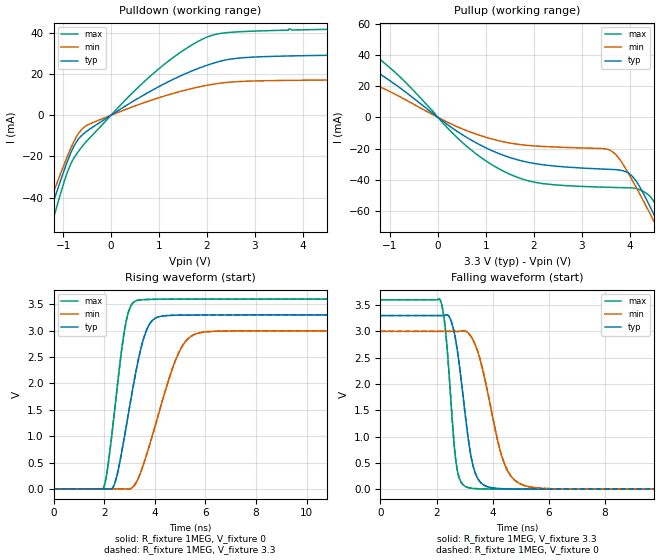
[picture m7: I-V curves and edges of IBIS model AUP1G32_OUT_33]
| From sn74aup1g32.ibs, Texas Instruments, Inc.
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[Model]   AUP1G32_OUT_33
Model_type  Output
Vref =   0
Rref =   1E6
Cref =   30p
Vmeas =   1.65
| variable   typ   min   max
C_comp   2.79pF   1.91pF   4.11pF
| C_pullup   3.16pF   1.91pF   4.11pF
| C_pulldown   2.42pF   2.21pF   2.99pF
[Temperature Range]   40   100   -40
| Ambient temperature   25   85   -40
[Voltage range]   3.3   3   3.6
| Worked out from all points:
|   slope of the pulldown table from 0 to 0.495 V, typ, clamps not added: 68.4 ohm
|   slope of the pullup table from 0 to 0.495 V, typ, clamps not added: 45.8 ohm
|   rising waveform, R_fixture 1MEG, V_fixture 0: 20-80 % time 764ps typ, 1.15ns min, 537ps max; typ from 0 V to 3.3 V
|   falling waveform, R_fixture 1MEG, V_fixture 3.3: 20-80 % time 476ps typ, 758ps min, 306ps max; typ from 3.3 V to 0 V
|   rising waveform, R_fixture 1MEG, V_fixture 3.3: 20-80 % time 763ps typ, 1.14ns min, 537ps max; typ from 0 V to 3.3 V
|   falling waveform, R_fixture 1MEG, V_fixture 0: 20-80 % time 476ps typ, 757ps min, 306ps max; typ from 3.3 V to 0 V
[Pulldown]
| AUP1G32_OUT_33
|   Voltage   I(typ)   I(min)   I(max)
-3.6V     -218.7mA   -196.3mA   -248.6mA
-1.515V   -64.37mA   -57.31mA   -75.82mA
-1.39V    -55.35mA   -49.29mA   -65.41mA
-1.275V   -47.14mA   -42mA      -55.89mA
-870mV    -19.93mA   -17.62mA   -25.18mA
-720mV    -12.85mA   -10.38mA   -18.82mA
-545mV    -8.444mA   -5.509mA   -13.51mA
940mV     13.13mA    8.018mA    21.36mA
1.5V      19.56mA    11.86mA    31.27mA
2.045V    24.53mA    14.67mA    38.2mA
3.1V      28.27mA    16.63mA    40.81mA
7.2V      29.73mA    17.36mA    42.67mA
[Pullup]
| AUP1G32_OUT_33
|   Voltage   I(typ)   I(min)   I(max)
-3.6V     42.87mA    27.21mA    57.96mA
-2.465V   31.52mA    19.46mA    45.92mA
-1.53V    32.86mA    22.06mA    44.96mA
-755mV    18.1mA     12.64mA    24.89mA
555mV     -11.98mA   -7.942mA   -17.3mA
1.65V     -27.07mA   -17.13mA   -38.31mA
3.61V     -33.32mA   -21.39mA   -44.82mA
4.08V     -38.63mA   -41.77mA   -45.28mA
4.375V    -54.25mA   -58.9mA    -49.24mA
4.565V    -66.24mA   -70.37mA   -57.33mA
4.775V    -80.02mA   -83.29mA   -71.37mA
7.2V      -250.7mA   -240.9mA   -257mA
[Ramp]
| AUP1G32_OUT_33
| variable   typ   min   max
dV/dt_r   1.98/7.65E-10   1.80/1.15E-09   2.16/5.38E-10
dV/dt_f   1.99/4.80E-10   1.81/7.63E-10   2.17/3.11E-10
R_load = 1MEG
[Rising Waveform]
| AUP1G32_OUT_33
R_fixture =   1MEG
C_fixture =   0
L_fixture =   0
V_fixture =   0
V_fixture_min = 0
V_fixture_max = 0
|   Time   V(typ)   V(min)   V(max)
0s        27.98nV    100.1nV    2.29nV
1.98ns    -66.42uV   3.044uV    25.81mV
2.4ns     81.9mV     -172.2uV   1.428V
2.825ns   1.053V     575.1uV    3.062V
3.295ns   2.319V     146.4mV    3.573V
3.625ns   2.947V     569.7mV    3.591V
3.955ns   3.215V     1.094V     3.595V
4.945ns   3.294V     2.578V     3.598V
5.775ns   3.297V     2.961V     3.599V
29.99ns   3.3V       3V         3.6V
[Falling Waveform]
| AUP1G32_OUT_33
R_fixture =   1MEG
C_fixture =   0
L_fixture =   0
V_fixture =   3.3
V_fixture_min = 3
V_fixture_max = 3.6
|   Time   V(typ)   V(min)   V(max)
0s        3.3V       3V         3.6V
2.135ns   3.3V       3V         3.592V
2.33ns    3.311V     3V         2.962V
2.515ns   3.203V     3V         1.667V
2.71ns    2.745V     2.998V     456.7mV
3.15ns    882.7mV    2.957V     27.1mV
3.535ns   149.4mV    2.499V     6.371mV
4.425ns   6.517mV    475.7mV    550.6uV
5.305ns   889.4uV    45.59mV    190.4uV
29.99ns   216.3uV    319.9uV    141.3uV
[Rising Waveform]
| AUP1G32_OUT_33
R_fixture =   1MEG
C_fixture =   0
L_fixture =   0
V_fixture =   3.3
V_fixture_min = 3
V_fixture_max = 3.6
|   Time   V(typ)   V(min)   V(max)
0s        216.3uV    319.9uV    141.3uV
1.98ns    149.9uV    322.8uV    25.96mV
2.4ns     82.16mV    147.6uV    1.429V
2.825ns   1.054V     895uV      3.063V
3.295ns   2.32V      146.8mV    3.573V
3.625ns   2.947V     570.6mV    3.591V
3.955ns   3.215V     1.095V     3.595V
4.945ns   3.294V     2.579V     3.598V
5.775ns   3.297V     2.961V     3.599V
29.99ns   3.3V       3V         3.6V
[Falling Waveform]
| AUP1G32_OUT_33
R_fixture =   1MEG
C_fixture =   0
L_fixture =   0
V_fixture =   0
V_fixture_min = 0
V_fixture_max = 0
|   Time   V(typ)   V(min)   V(max)
0s        3.3V       3V         3.6V
2.135ns   3.3V       3V         3.591V
2.33ns    3.311V     3V         2.962V
2.515ns   3.203V     3V         1.667V
2.71ns    2.744V     2.998V     456.2mV
3.15ns    882mV      2.957V     26.94mV
3.535ns   149.1mV    2.498V     6.225mV
4.425ns   6.288mV    474.9mV    408.7uV
5.305ns   670.4uV    45.13mV    49.02uV
29.99ns   1.599nV    86.09nV    -14.25nV
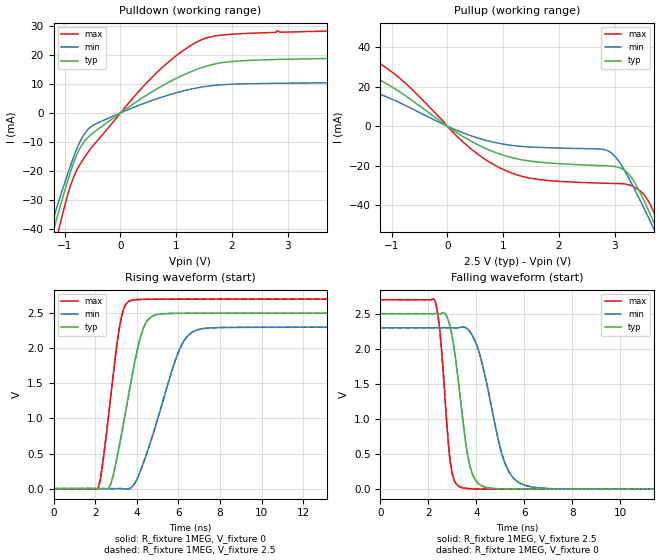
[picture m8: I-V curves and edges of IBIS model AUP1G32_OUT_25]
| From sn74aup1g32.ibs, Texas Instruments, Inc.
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[Model]   AUP1G32_OUT_25
Model_type  Output
Vref =   0
Rref =   1E6
Cref =   30p
Vmeas =   1.25
| variable   typ   min   max
C_comp   2.83pF   1.96pF   4.14pF
| C_pullup   3.16pF   1.96pF   4.14pF
| C_pulldown   2.51pF   2.22pF   3.08pF
[Temperature Range]   40   100   -40
| Ambient temperature   25   85   -40
[Voltage range]   2.5   2.3   2.7
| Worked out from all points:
|   slope of the pulldown table from 0 to 0.375 V, typ, clamps not added: 75.2 ohm
|   slope of the pullup table from 0 to 0.375 V, typ, clamps not added: 55.1 ohm
|   rising waveform, R_fixture 1MEG, V_fixture 0: 20-80 % time 957ps typ, 1.44ns min, 656ps max; typ from 0 V to 2.5 V
|   falling waveform, R_fixture 1MEG, V_fixture 2.5: 20-80 % time 558ps typ, 899ps min, 360ps max; typ from 2.5 V to 0 V
|   rising waveform, R_fixture 1MEG, V_fixture 2.5: 20-80 % time 957ps typ, 1.44ns min, 656ps max; typ from 0 V to 2.5 V
|   falling waveform, R_fixture 1MEG, V_fixture 0: 20-80 % time 558ps typ, 899ps min, 360ps max; typ from 2.5 V to 0 V
[Pulldown]
| AUP1G32_OUT_25
|   Voltage   I(typ)   I(min)   I(max)
-3.6V     -214mA     -193.5mA   -239.7mA
-1.26V    -44.55mA   -39.92mA   -52.42mA
-1.205V   -40.74mA   -36.52mA   -48.02mA
-1.115V   -34.57mA   -31.02mA   -40.91mA
-800mV    -15.22mA   -13.22mA   -20.4mA
-685mV    -10.84mA   -8.445mA   -16.54mA
-540mV    -7.689mA   -4.911mA   -12.5mA
675mV     8.558mA    5.038mA    14.35mA
1.105V    12.9mA     7.5mA      21.28mA
1.52V     16.03mA    9.129mA    25.76mA
2.805V    18.45mA    10.24mA    28.28mA
7.2V      19.61mA    10.73mA    29.61mA
[Pullup]
| AUP1G32_OUT_25
|   Voltage   I(typ)   I(min)   I(max)
-3.6V     37.27mA    23.46mA    50.39mA
-2.36V    24.67mA    15.19mA    35.64mA
-1.425V   26mA       17.18mA    35.59mA
-760mV    15.58mA    10.62mA    21.96mA
405mV     -7.279mA   -4.651mA   -11.04mA
1.05V     -15.07mA   -9.293mA   -22.54mA
2.845V    -20.04mA   -12.07mA   -28.88mA
3.17V     -22.17mA   -22.09mA   -29.2mA
3.455V    -33.67mA   -37.48mA   -32.73mA
3.685V    -47.61mA   -50.92mA   -42.5mA
3.82V     -56.28mA   -59.04mA   -51.47mA
7.2V      -294.7mA   -278.7mA   -311.5mA
[Ramp]
| AUP1G32_OUT_25
| variable   typ   min   max
dV/dt_r   1.50/9.61E-10   1.38/1.45E-09   1.62/6.58E-10
dV/dt_f   1.51/5.64E-10   1.39/9.07E-10   1.63/3.64E-10
R_load = 1MEG
[Rising Waveform]
| AUP1G32_OUT_25
R_fixture =   1MEG
C_fixture =   0
L_fixture =   0
V_fixture =   0
V_fixture_min = 0
V_fixture_max = 0
|   Time   V(typ)   V(min)   V(max)
0s        21.76nV    95.42nV    1.586nV
2.155ns   -85.48uV   3.158uV    20.35mV
2.705ns   35.71mV    -150.9uV   1.194V
3.18ns    635.7mV    1.828mV    2.314V
3.725ns   1.522V     13.5mV     2.68V
4.19ns    2.167V     263.2mV    2.695V
4.59ns    2.422V     597.5mV    2.697V
6.045ns   2.497V     1.973V     2.699V
6.975ns   2.498V     2.266V     2.7V
32ns      2.5V       2.3V       2.7V
[Falling Waveform]
| AUP1G32_OUT_25
R_fixture =   1MEG
C_fixture =   0
L_fixture =   0
V_fixture =   2.5
V_fixture_min = 2.3
V_fixture_max = 2.7
|   Time   V(typ)   V(min)   V(max)
0s        2.5V       2.3V       2.7V
2.27ns    2.5V       2.3V       2.688V
2.485ns   2.499V     2.3V       2.234V
2.94ns    2.263V     2.3V       328.2mV
3.435ns   996.6mV    2.311V     19.24mV
3.71ns    366.9mV    2.254V     7.239mV
4.04ns    95.23mV    2.03V      2.585mV
5.18ns    3.119mV    384.6mV    214.1uV
6.18ns    482.4uV    40.71mV    124.8uV
32ns      178.6uV    276uV      112.4uV
[Rising Waveform]
| AUP1G32_OUT_25
R_fixture =   1MEG
C_fixture =   0
L_fixture =   0
V_fixture =   2.5
V_fixture_min = 2.3
V_fixture_max = 2.7
|   Time   V(typ)   V(min)   V(max)
0s        178.6uV    276.1uV    112.4uV
2.155ns   93.1uV     279.2uV    20.47mV
2.705ns   35.92mV    125uV      1.195V
3.18ns    636.4mV    2.104mV    2.315V
3.725ns   1.523V     13.81mV    2.68V
4.19ns    2.168V     263.9mV    2.695V
4.59ns    2.422V     598.7mV    2.697V
6.045ns   2.497V     1.974V     2.699V
6.975ns   2.499V     2.267V     2.7V
32ns      2.5V       2.3V       2.7V
[Falling Waveform]
| AUP1G32_OUT_25
R_fixture =   1MEG
C_fixture =   0
L_fixture =   0
V_fixture =   0
V_fixture_min = 0
V_fixture_max = 0
|   Time   V(typ)   V(min)   V(max)
0s        2.5V       2.3V       2.7V
2.27ns    2.5V       2.3V       2.688V
2.485ns   2.499V     2.3V       2.234V
2.94ns    2.263V     2.3V       327.9mV
3.435ns   996mV      2.311V     19.12mV
3.71ns    366.5mV    2.254V     7.12mV
4.04ns    94.95mV    2.03V      2.47mV
5.18ns    2.932mV    383.9mV    101.4uV
6.18ns    302uV      40.25mV    12.4uV
32ns      -2.304nV   29.56nV    -15.94nV
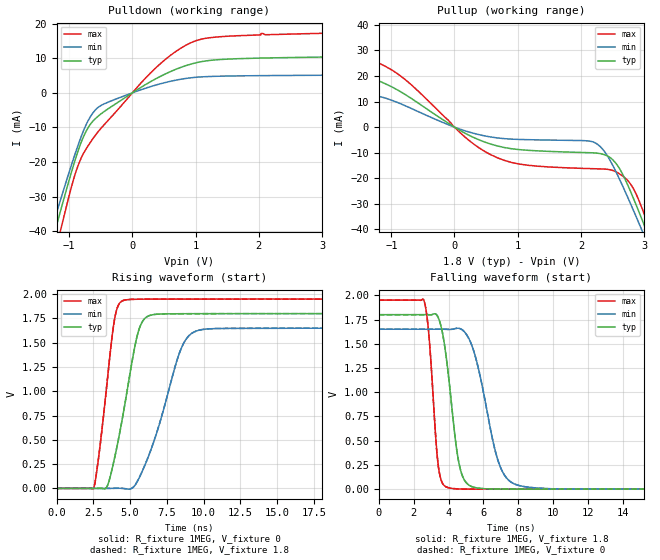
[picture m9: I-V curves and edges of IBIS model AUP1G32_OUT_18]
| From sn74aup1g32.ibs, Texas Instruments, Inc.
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[Model]   AUP1G32_OUT_18
Model_type  Output
Vref =   0
Rref =   1E6
Cref =   30p
Vmeas =   0.9
| variable   typ   min   max
C_comp   2.87pF   2.03pF   4.09pF
| C_pullup   3.13pF   2.03pF   4.09pF
| C_pulldown   2.60pF   2.23pF   3.12pF
[Temperature Range]   40   100   -40
| Ambient temperature   25   85   -40
[Voltage range]   1.8   1.65   1.95
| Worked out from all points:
|   slope of the pulldown table from 0 to 0.27 V, typ, clamps not added: 88.6 ohm
|   slope of the pullup table from 0 to 0.27 V, typ, clamps not added: 73.6 ohm
|   rising waveform, R_fixture 1MEG, V_fixture 0: 20-80 % time 1.28ns typ, 1.94ns min, 857ps max; typ from 0 V to 1.8 V
|   falling waveform, R_fixture 1MEG, V_fixture 1.8: 20-80 % time 699ps typ, 1.17ns min, 439ps max; typ from 1.8 V to 0 V
|   rising waveform, R_fixture 1MEG, V_fixture 1.8: 20-80 % time 1.28ns typ, 1.94ns min, 857ps max; typ from 0 V to 1.8 V
|   falling waveform, R_fixture 1MEG, V_fixture 0: 20-80 % time 699ps typ, 1.17ns min, 439ps max; typ from 1.8 V to 0 V
[Pulldown]
| AUP1G32_OUT_18
|   Voltage   I(typ)   I(min)   I(max)
-3.6V     -208.6mA   -189.9mA   -231.7mA
-1.27V    -43.16mA   -39.01mA   -50.14mA
-1.215V   -39.42mA   -35.66mA   -45.88mA
-1.125V   -33.38mA   -30.25mA   -38.97mA
-850mV    -16.31mA   -14.68mA   -20.63mA
-710mV    -10.41mA   -8.408mA   -15.6mA
-555mV    -6.973mA   -4.411mA   -11.55mA
360mV     3.96mA     2.185mA    7.039mA
705mV     6.927mA    3.722mA    12.18mA
1.03V     8.784mA    4.527mA    15.22mA
2.045V    10.05mA    4.967mA    17.16mA
7.2V      11.18mA    5.355mA    18.77mA
[Pullup]
| AUP1G32_OUT_18
|   Voltage   I(typ)   I(min)   I(max)
-3.6V     32.08mA    19.68mA    43.87mA
-3.16V    27.18mA    16.59mA    37.99mA
-2.12V    17.93mA    10.75mA    26.53mA
-1.525V   19.28mA    11.75mA    27.77mA
-1.155V   17.65mA    11.81mA    24.55mA
680mV     -7.373mA   -4.228mA   -12mA
2.185V    -10.05mA   -5.721mA   -16.26mA
2.485V    -12.35mA   -14.1mA    -16.81mA
2.725V    -21.81mA   -26.61mA   -20.47mA
2.94V     -34.55mA   -38.91mA   -30.08mA
3.085V    -43.74mA   -47.5mA    -39.77mA
7.2V      -334.8mA   -315.6mA   -357.6mA
[Ramp]
| AUP1G32_OUT_18
| variable   typ   min   max
dV/dt_r   1.08/1.29E-09   0.99/1.96E-09   1.17/8.60E-10
dV/dt_f   1.09/7.06E-10   1.00/1.18E-09   1.18/4.47E-10
R_load = 1MEG
[Rising Waveform]
| AUP1G32_OUT_18
R_fixture =   1MEG
C_fixture =   0
L_fixture =   0
V_fixture =   0
V_fixture_min = 0
V_fixture_max = 0
|   Time   V(typ)   V(min)   V(max)
0s        18.54nV    100.1nV    1.179nV
2.54ns    -93.92uV   3.907uV    10.53mV
3.39ns    8.296mV    -118.8uV   1.021V
3.905ns   282.8mV    695.5uV    1.702V
4.525ns   760.3mV    -515.6uV   1.935V
5.385ns   1.505V     43.32mV    1.948V
5.905ns   1.733V     201.9mV    1.949V
8.41ns    1.799V     1.415V     1.95V
9.5ns     1.799V     1.621V     1.95V
34ns      1.8V       1.65V      1.95V
[Falling Waveform]
| AUP1G32_OUT_18
R_fixture =   1MEG
C_fixture =   0
L_fixture =   0
V_fixture =   1.8
V_fixture_min = 1.65
V_fixture_max = 1.95
|   Time   V(typ)   V(min)   V(max)
0s        1.8V       1.65V      1.95V
2.6ns     1.8V       1.65V      1.943V
2.875ns   1.799V     1.65V      1.593V
3.415ns   1.768V     1.65V      241.2mV
3.96ns    1.228V     1.648V     16.81mV
4.49ns    379.8mV    1.66V      3.41mV
4.91ns    92.97mV    1.623V     1.042mV
6.87ns    893.4uV    274.3mV    98.75uV
7.94ns    248.3uV    42.33mV    91.74uV
34ns      149.3uV    244.2uV    89.89uV
[Rising Waveform]
| AUP1G32_OUT_18
R_fixture =   1MEG
C_fixture =   0
L_fixture =   0
V_fixture =   1.8
V_fixture_min = 1.65
V_fixture_max = 1.95
|   Time   V(typ)   V(min)   V(max)
0s        149.3uV    244uV      89.92uV
2.54ns    55.38uV    247.8uV    10.64mV
3.39ns    8.482mV    125.1uV    1.022V
3.905ns   283.3mV    939.5uV    1.703V
4.525ns   761.2mV    -272.5uV   1.935V
5.38ns    1.502V     42.59mV    1.948V
5.9ns     1.732V     200.9mV    1.949V
8.41ns    1.799V     1.416V     1.95V
9.5ns     1.799V     1.621V     1.95V
34ns      1.8V       1.65V      1.95V
[Falling Waveform]
| AUP1G32_OUT_18
R_fixture =   1MEG
C_fixture =   0
L_fixture =   0
V_fixture =   0
V_fixture_min = 0
V_fixture_max = 0
|   Time   V(typ)   V(min)   V(max)
0s        1.8V       1.65V      1.95V
2.6ns     1.8V       1.65V      1.943V
2.875ns   1.799V     1.65V      1.592V
3.415ns   1.768V     1.65V      240.9mV
3.96ns    1.227V     1.648V     16.71mV
4.49ns    379.3mV    1.66V      3.315mV
4.91ns    92.7mV     1.623V     950.2uV
6.87ns    739.9uV    273.8mV    8.78uV
7.94ns    98.09uV    41.9mV     1.807uV
34ns      -28.35nV   253.6nV    -31.24nV
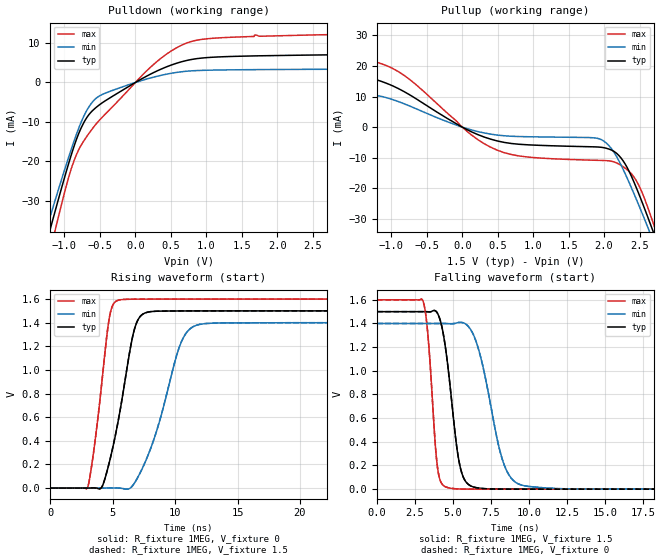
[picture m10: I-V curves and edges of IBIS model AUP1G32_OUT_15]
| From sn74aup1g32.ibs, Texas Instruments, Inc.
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[Model]   AUP1G32_OUT_15
Model_type  Output
Vref =   0
Rref =   1E6
Cref =   30p
Vmeas =   0.75
| variable   typ   min   max
C_comp   2.87pF   2.09pF   4.01pF
| C_pullup   3.08pF   2.09pF   4.01pF
| C_pulldown   2.65pF   2.24pF   3.14pF
[Temperature Range]   40   100   -40
| Ambient temperature   25   85   -40
[Voltage range]   1.5   1.4   1.6
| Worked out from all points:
|   slope of the pulldown table from 0 to 0.225 V, typ, clamps not added: 101 ohm
|   slope of the pullup table from 0 to 0.225 V, typ, clamps not added: 90.4 ohm
|   rising waveform, R_fixture 1MEG, V_fixture 0: 20-80 % time 1.53ns typ, 2.27ns min, 1.03ns max; typ from 0 V to 1.5 V
|   falling waveform, R_fixture 1MEG, V_fixture 1.5: 20-80 % time 813ps typ, 1.37ns min, 506ps max; typ from 1.5 V to 0 V
|   rising waveform, R_fixture 1MEG, V_fixture 1.5: 20-80 % time 1.53ns typ, 2.27ns min, 1.03ns max; typ from 0 V to 1.5 V
|   falling waveform, R_fixture 1MEG, V_fixture 0: 20-80 % time 813ps typ, 1.37ns min, 506ps max; typ from 1.5 V to 0 V
[Pulldown]
| AUP1G32_OUT_15
|   Voltage   I(typ)   I(min)   I(max)
-3.6V     -206.1mA   -188.4mA   -227.8mA
-1.265V   -41.59mA   -37.94mA   -47.65mA
-1.21V    -37.9mA    -34.62mA   -43.48mA
-1.11V    -31.29mA   -28.67mA   -36mA
-945mV    -20.84mA   -19.21mA   -24.37mA
-855mV    -15.7mA    -14.39mA   -19.43mA
-720mV    -9.972mA   -8.297mA   -14.65mA
-570mV    -6.595mA   -4.269mA   -10.91mA
260mV     2.544mA    1.373mA    4.642mA
810mV     5.906mA    2.979mA    10.53mA
1.69V     6.763mA    3.269mA    12.06mA
7.2V      7.827mA    3.609mA    13.77mA
[Pullup]
| AUP1G32_OUT_15
|   Voltage   I(typ)   I(min)   I(max)
-3.6V     29.66mA    17.92mA    40.73mA
-2.925V   22.54mA    13.62mA    31.92mA
-2.13V    15.77mA    9.482mA    23.18mA
-1.075V   14.38mA    9.657mA    20.14mA
130mV     -1.525mA   -910.1uA   -2.565mA
590mV     -4.979mA   -2.819mA   -8.32mA
1.925V    -6.506mA   -3.765mA   -10.85mA
2.175V    -8.513mA   -9.57mA    -11.67mA
2.395V    -16.55mA   -20.31mA   -15.49mA
2.615V    -29.32mA   -32.63mA   -26.15mA
2.72V     -35.89mA   -38.74mA   -33.2mA
7.2V      -352.6mA   -330.3mA   -379.5mA
[Ramp]
| AUP1G32_OUT_15
| variable   typ   min   max
dV/dt_r   0.90/1.54E-09   0.85/2.30E-09   0.96/1.04E-09
dV/dt_f   0.91/8.23E-10   0.85/1.38E-09   0.96/5.13E-10
R_load = 1MEG
[Rising Waveform]
| AUP1G32_OUT_15
R_fixture =   1MEG
C_fixture =   0
L_fixture =   0
V_fixture =   0
V_fixture_min = 0
V_fixture_max = 0
|   Time   V(typ)   V(min)   V(max)
0s        18.11nV    107.8nV    1.037nV
3.005ns   -94.98uV   957.3nV    9.569mV
4.08ns    1.214mV    -121.4uV   843.6mV
4.695ns   202.7mV    740.6uV    1.417V
5.37ns    528.2mV    598.8uV    1.587V
6.54ns    1.253V     12.5mV     1.599V
7.12ns    1.441V     112.2mV    1.599V
10.39ns   1.499V     1.207V     1.6V
11.61ns   1.5V       1.374V     1.6V
38ns      1.5V       1.4V       1.6V
[Falling Waveform]
| AUP1G32_OUT_15
R_fixture =   1MEG
C_fixture =   0
L_fixture =   0
V_fixture =   1.5
V_fixture_min = 1.4
V_fixture_max = 1.6
|   Time   V(typ)   V(min)   V(max)
0s        1.5V       1.4V       1.6V
3.025ns   1.5V       1.4V       1.588V
3.355ns   1.499V     1.4V       1.287V
3.965ns   1.488V     1.4V       194.1mV
4.59ns    1.111V     1.399V     15.45mV
5.765ns   78.02mV    1.401V     700.8uV
6.715ns   8.85mV     1.166V     135uV
8.315ns   541.2uV    224.6mV    83.1uV
9.46ns    195.2uV    36.33mV    81.22uV
38ns      139.7uV    237.8uV    80.72uV
[Rising Waveform]
| AUP1G32_OUT_15
R_fixture =   1MEG
C_fixture =   0
L_fixture =   0
V_fixture =   1.5
V_fixture_min = 1.4
V_fixture_max = 1.6
|   Time   V(typ)   V(min)   V(max)
0s        139.7uV    237.8uV    80.77uV
3.005ns   44.69uV    238.6uV    9.687mV
4.08ns    1.402mV    116.3uV    844.3mV
4.695ns   203.2mV    978.2uV    1.418V
5.37ns    529.2mV    834.4uV    1.587V
6.54ns    1.254V     12.93mV    1.599V
7.12ns    1.441V     113mV      1.599V
10.39ns   1.499V     1.208V     1.6V
11.61ns   1.5V       1.375V     1.6V
38ns      1.5V       1.4V       1.6V
[Falling Waveform]
| AUP1G32_OUT_15
R_fixture =   1MEG
C_fixture =   0
L_fixture =   0
V_fixture =   0
V_fixture_min = 0
V_fixture_max = 0
|   Time   V(typ)   V(min)   V(max)
0s        1.5V       1.4V       1.6V
3.025ns   1.5V       1.4V       1.588V
3.355ns   1.499V     1.4V       1.286V
3.965ns   1.488V     1.4V       193.9mV
4.59ns    1.11V      1.399V     15.36mV
5.765ns   77.76mV    1.401V     618.7uV
6.715ns   8.672mV    1.165V     53.95uV
8.315ns   398.5uV    224mV      2.312uV
9.46ns    54.99uV    36.04mV    444.5nV
38ns      89.79nV    146.6nV    -48.35nV
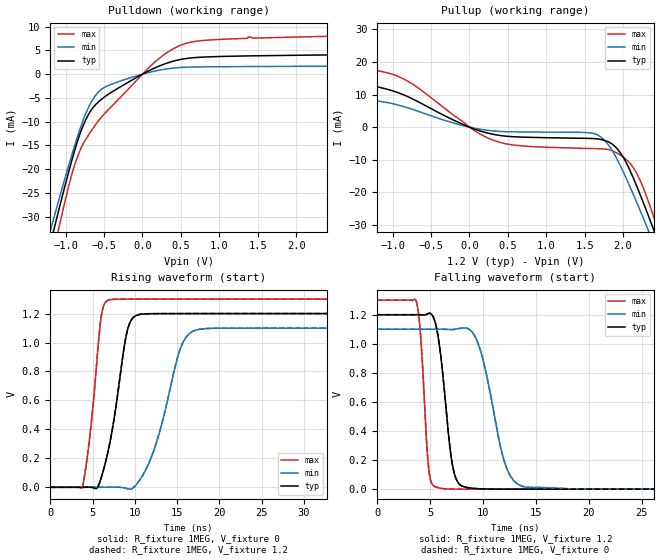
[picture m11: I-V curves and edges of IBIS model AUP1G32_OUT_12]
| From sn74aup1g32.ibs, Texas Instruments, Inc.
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[Model]   AUP1G32_OUT_12
Model_type  Output
Vref =   0
Rref =   1E6
Cref =   30p
Vmeas =   0.6
| variable   typ   min   max
C_comp   2.83pF   2.12pF   3.87pF
| C_pullup   3.00pF   2.12pF   3.87pF
| C_pulldown   2.67pF   2.23pF   3.17pF
[Temperature Range]   40   100   -40
| Ambient temperature   25   85   -40
[Voltage range]   1.2   1.1   1.3
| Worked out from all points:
|   slope of the pulldown table from 0 to 0.18 V, typ, clamps not added: 125 ohm
|   slope of the pullup table from 0 to 0.18 V, typ, clamps not added: 123 ohm
|   rising waveform, R_fixture 1MEG, V_fixture 0: 20-80 % time 1.91ns typ, 2.94ns min, 1.28ns max; typ from 0 V to 1.2 V
|   falling waveform, R_fixture 1MEG, V_fixture 1.2: 20-80 % time 1.02ns typ, 1.86ns min, 609ps max; typ from 1.2 V to 0 V
|   rising waveform, R_fixture 1MEG, V_fixture 1.2: 20-80 % time 1.91ns typ, 2.94ns min, 1.28ns max; typ from 0 V to 1.2 V
|   falling waveform, R_fixture 1MEG, V_fixture 0: 20-80 % time 1.02ns typ, 1.86ns min, 609ps max; typ from 1.2 V to 0 V
[Pulldown]
| AUP1G32_OUT_12
|   Voltage   I(typ)   I(min)   I(max)
-3.6V     -203.6mA   -186.6mA   -224.6mA
-1.215V   -36.77mA   -33.88mA   -41.55mA
-1.165V   -33.49mA   -30.92mA   -37.89mA
-1.08V    -28mA      -25.95mA   -31.76mA
-930mV    -18.76mA   -17.53mA   -21.68mA
-835mV    -13.58mA   -12.59mA   -16.93mA
-695mV    -8.261mA   -6.747mA   -12.62mA
-560mV    -5.647mA   -3.535mA   -9.551mA
195mV     1.548mA    762.4uA    3.019mA
610mV     3.376mA    1.481mA    6.659mA
1.385V    3.84mA     1.603mA    7.836mA
7.2V      4.761mA    1.852mA    9.574mA
[Pullup]
| AUP1G32_OUT_12
|   Voltage   I(typ)   I(min)   I(max)
-3.6V     26.64mA    8.231mA    37.82mA
-3.07V    21.45mA    10.47mA    31mA
-2.05V    13.05mA    7.514mA    19.68mA
-955mV    10.79mA    6.947mA    15.81mA
400mV     -2.561mA   -1.314mA   -4.679mA
1.61V     -3.491mA   -1.891mA   -6.566mA
1.87V     -5.387mA   -7.563mA   -7.321mA
2.095V    -13.49mA   -18.49mA   -11.17mA
2.33V     -27.16mA   -31.66mA   -22.8mA
2.44V     -34.07mA   -38.08mA   -30.25mA
2.51V     -38.55mA   -42.22mA   -35.17mA
7.2V      -371mA     -348.5mA   -398.6mA
[Ramp]
| AUP1G32_OUT_12
| variable   typ   min   max
dV/dt_r   0.73/1.93E-09   0.67/3.00E-09   0.78/1.28E-09
dV/dt_f   0.73/1.03E-09   0.67/1.88E-09   0.78/6.17E-10
R_load = 1MEG
[Rising Waveform]
| AUP1G32_OUT_12
R_fixture =   1MEG
C_fixture =   0
L_fixture =   0
V_fixture =   0
V_fixture_min = 0
V_fixture_max = 0
|   Time   V(typ)   V(min)   V(max)
0s        18.95nV    130.2nV    950.7pV
3.815ns   -74.41uV   262.2nV    5.371mV
5.995ns   60.21mV    -130.5uV   1.164V
6.845ns   250mV      661.8uV    1.292V
9.01ns    1.055V     -7.854mV   1.3V
10.33ns   1.19V      29.93mV    1.3V
12.54ns   1.199V     304.7mV    1.3V
15.41ns   1.2V       961.5mV    1.3V
17.1ns    1.2V       1.083V     1.3V
60ns      1.2V       1.1V       1.3V
[Falling Waveform]
| AUP1G32_OUT_12
R_fixture =   1MEG
C_fixture =   0
L_fixture =   0
V_fixture =   1.2
V_fixture_min = 1.1
V_fixture_max = 1.3
|   Time   V(typ)   V(min)   V(max)
0s        1.2V       1.1V       1.3V
3.7ns     1.2V       1.1V       1.292V
4.87ns    1.209V     1.1V       140.9mV
5.64ns    1.098V     1.1V       12.67mV
7.095ns   174.5mV    1.098V     530.8uV
8.23ns    15.55mV    1.109V     105.8uV
9.765ns   2.283mV    952.1mV    76.42uV
12.18ns   188.2uV    155.4mV    74.88uV
13.76ns   140.5uV    18.92mV    74.79uV
60ns      135uV      244.3uV    74.83uV
[Rising Waveform]
| AUP1G32_OUT_12
R_fixture =   1MEG
C_fixture =   0
L_fixture =   0
V_fixture =   1.2
V_fixture_min = 1.1
V_fixture_max = 1.3
|   Time   V(typ)   V(min)   V(max)
0s        135uV      244.2uV    74.83uV
3.815ns   60.66uV    244.3uV    5.507mV
5.995ns   60.66mV    113.8uV    1.165V
6.845ns   250.9mV    905.2uV    1.292V
9.01ns    1.056V     -7.58mV    1.3V
10.33ns   1.191V     30.69mV    1.3V
12.53ns   1.199V     305.5mV    1.3V
15.41ns   1.2V       961.4mV    1.3V
17.09ns   1.2V       1.083V     1.3V
60ns      1.2V       1.1V       1.3V
[Falling Waveform]
| AUP1G32_OUT_12
R_fixture =   1MEG
C_fixture =   0
L_fixture =   0
V_fixture =   0
V_fixture_min = 0
V_fixture_max = 0
|   Time   V(typ)   V(min)   V(max)
0s        1.2V       1.1V       1.3V
3.7ns     1.2V       1.1V       1.291V
4.865ns   1.209V     1.1V       144mV
5.64ns    1.098V     1.1V       12.58mV
7.095ns   174.1mV    1.098V     455uV
8.23ns    15.36mV    1.109V     30.82uV
9.76ns    2.143mV    952.4mV    1.582uV
12.18ns   52.53uV    154.6mV    48.95nV
13.76ns   5.394uV    18.75mV    -44.72nV
60ns      7.983nV    205.1nV    -3.29nV
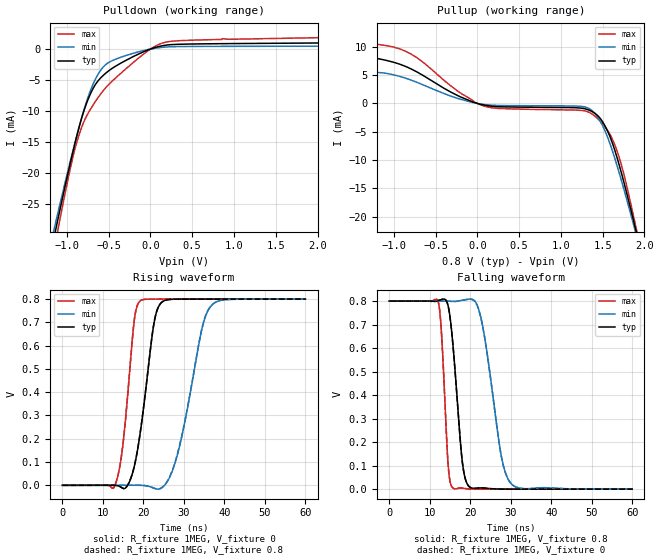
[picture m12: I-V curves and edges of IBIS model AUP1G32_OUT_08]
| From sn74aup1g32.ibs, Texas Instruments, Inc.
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[Model]   AUP1G32_OUT_08
Model_type  Output
Vref =   0
Rref =   1E6
Cref =   30p
Vmeas =   0.4
| variable   typ   min   max
C_comp   2.70pF   2.19pF   3.31pF
| C_pullup   2.75pF   2.20pF   3.31pF
| C_pulldown   2.64pF   2.19pF   3.08pF
[Temperature Range]   40   100   -40
| Ambient temperature   25   85   -40
[Voltage range]   0.8   0.8   0.8
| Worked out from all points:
|   slope of the pulldown table from 0 to 0.12 V, typ, clamps not added: 257 ohm
|   slope of the pullup table from 0 to 0.12 V, typ, clamps not added: 309 ohm
|   rising waveform, R_fixture 1MEG, V_fixture 0: 20-80 % time 3.5ns typ, 5.26ns min, 2.5ns max; typ from 0 V to 0.8 V
|   falling waveform, R_fixture 1MEG, V_fixture 0.8: 20-80 % time 2.19ns typ, 3.87ns min, 1.35ns max; typ from 0.8 V to 0 V
|   rising waveform, R_fixture 1MEG, V_fixture 0.8: 20-80 % time 3.5ns typ, 5.25ns min, 2.5ns max; typ from 0 V to 0.8 V
|   falling waveform, R_fixture 1MEG, V_fixture 0: 20-80 % time 2.19ns typ, 3.87ns min, 1.35ns max; typ from 0.8 V to 0 V
[Pulldown]
| AUP1G32_OUT_08
|   Voltage   I(typ)   I(min)   I(max)
-3.6V     -200.3mA   -184.7mA   -219.1mA
-1.155V   -30.43mA   -29.11mA   -32.45mA
-1.105V   -27.26mA   -26.22mA   -28.93mA
-940mV    -17.24mA   -17.01mA   -18.09mA
-865mV    -13.13mA   -13.1mA    -14.27mA
-745mV    -8.043mA   -7.657mA   -10.32mA
-630mV    -5.174mA   -4.128mA   -7.88mA
-470mV    -3.218mA   -1.946mA   -5.328mA
5mV       23.8uA     12.51uA    45.54uA
210mV     667.8uA    349.8uA    1.181mA
875mV     872.7uA    431.9uA    1.671mA
7.2V      1.459mA    578.6uA    3.138mA
[Pullup]
| AUP1G32_OUT_08
|   Voltage   I(typ)   I(min)   I(max)
-3.6V     2.784mA    339.3uA    9.474mA
-2.56V    3.921mA    664.1uA    11.14mA
-2.01V    6.261mA    1.27mA     13.38mA
-1.185V   7.904mA    5.467mA    10.42mA
-800mV    6.148mA    4.167mA    8.778mA
80mV      -287uA     -177.3uA   -461.9uA
1.285V    -921uA     -607uA     -1.305mA
1.455V    -2.355mA   -2.736mA   -2.902mA
1.625V    -7.333mA   -8.725mA   -6.56mA
1.74V     -13.09mA   -14.38mA   -11.68mA
1.905V    -22.78mA   -23.32mA   -22.23mA
7.2V      -396.8mA   -367.4mA   -431.7mA
[Ramp]
| AUP1G32_OUT_08
| variable   typ   min   max
dV/dt_r   0.49/3.59E-09   0.49/5.40E-09   0.49/2.56E-09
dV/dt_f   0.49/2.22E-09   0.48/3.91E-09   0.48/1.37E-09
R_load = 1MEG
[Rising Waveform]
| AUP1G32_OUT_08
R_fixture =   1MEG
C_fixture =   0
L_fixture =   0
V_fixture =   0
V_fixture_min = 0
V_fixture_max = 0
|   Time   V(typ)   V(min)   V(max)
0s        28.64nV    214.4nV    1.117nV
12.94ns   5.503uV    -75.4uV    -1.079mV
16.45ns   11.28mV    352.8uV    455.9mV
17.84ns   88.49mV    306.6uV    721.1mV
19.22ns   226.5mV    28.53uV    792.3mV
22.56ns   690.2mV    -12.2mV    799.8mV
24.62ns   787.5mV    -9.803mV   799.9mV
28.42ns   799.5mV    133.1mV    799.9mV
36.52ns   799.8mV    766.3mV    799.9mV
60ns      799.8mV    799.7mV    799.9mV
[Falling Waveform]
| AUP1G32_OUT_08
R_fixture =   1MEG
C_fixture =   0
L_fixture =   0
V_fixture =   0.8
V_fixture_min = 0.8
V_fixture_max = 0.8
|   Time   V(typ)   V(min)   V(max)
0s        800mV      800mV      800mV
12.05ns   801.8mV    800mV      799.6mV
14.57ns   776.2mV    799.6mV    95.66mV
15.71ns   614.8mV    798.7mV    4.816mV
18.01ns   120.4mV    803.4mV    4.72mV
19.81ns   9.801mV    808.4mV    935.5uV
22.67ns   5.391mV    726.1mV    110.6uV
27.61ns   496.8uV    146.1mV    87.26uV
30.02ns   216.3uV    25.03mV    87.1uV
60ns      167uV      319.3uV    87.04uV
[Rising Waveform]
| AUP1G32_OUT_08
R_fixture =   1MEG
C_fixture =   0
L_fixture =   0
V_fixture =   0.8
V_fixture_min = 0.8
V_fixture_max = 0.8
|   Time   V(typ)   V(min)   V(max)
0s        166.8uV    317.5uV    87.04uV
12.93ns   168.8uV    242.5uV    -834.7uV
16.44ns   11.81mV    664.6uV    455.1mV
17.84ns   89mV       613.3uV    720.8mV
19.22ns   227.5mV    332.6uV    792.5mV
22.55ns   690.2mV    -11.48mV   799.9mV
24.61ns   787.7mV    -8.732mV   800mV
28.4ns    799.7mV    134.1mV    800mV
36.49ns   800mV      766.7mV    800mV
60ns      800mV      800mV      800mV
[Falling Waveform]
| AUP1G32_OUT_08
R_fixture =   1MEG
C_fixture =   0
L_fixture =   0
V_fixture =   0
V_fixture_min = 0
V_fixture_max = 0
|   Time   V(typ)   V(min)   V(max)
0s        799.8mV    799.7mV    799.9mV
12.05ns   801.6mV    799.7mV    799.1mV
14.57ns   775.8mV    799.3mV    96.18mV
15.71ns   614.7mV    798.4mV    4.756mV
18.01ns   120.2mV    803.1mV    4.635mV
19.81ns   9.622mV    807.7mV    849.7uV
22.67ns   5.199mV    724.8mV    23.54uV
27.59ns   328.4uV    145.9mV    213.5nV
30ns      49.23uV    24.7mV     61.29nV
60ns      193.1nV    1.974uV    2.125nV
